VERSION 5.7 ;
  NAMESCASESENSITIVE ON ;
  NOWIREEXTENSIONATPIN ON ;
  DIVIDERCHAR "/" ;
  BUSBITCHARS "[]" ;
UNITS
  DATABASE MICRONS 200 ;
END UNITS

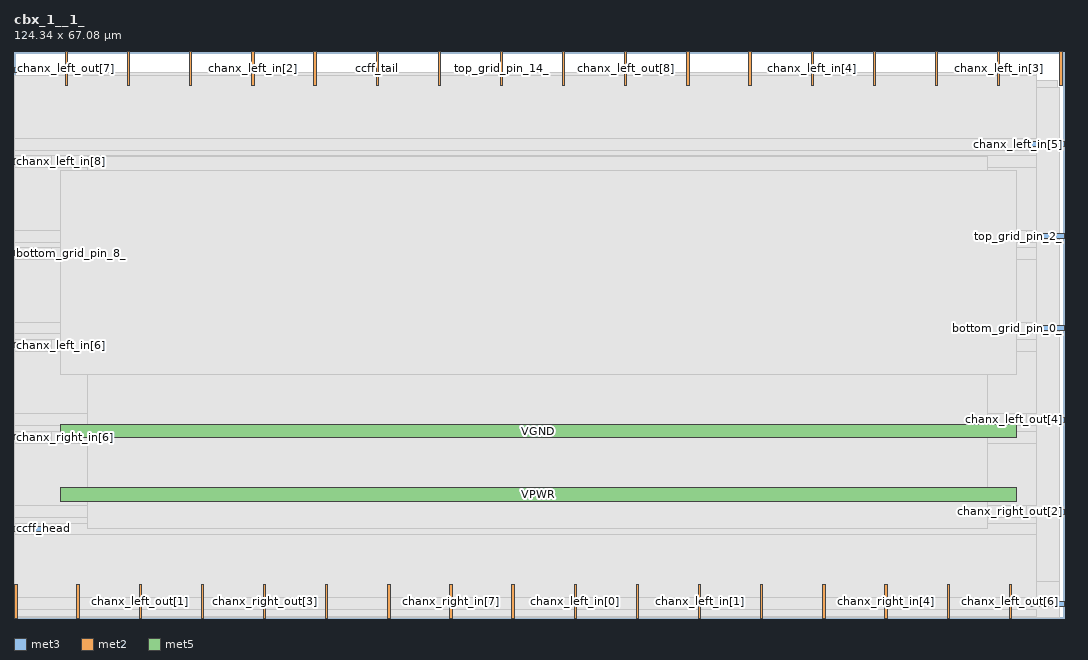
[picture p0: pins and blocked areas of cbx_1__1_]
MACRO cbx_1__1_
  CLASS BLOCK ;
  FOREIGN cbx_1__1_ ;
  ORIGIN 0.000 0.000 ;
  SIZE 124.340 BY 67.080 ;
  PIN bottom_grid_pin_0_
    DIRECTION OUTPUT TRISTATE ;
    PORT
      LAYER met3 ;
        RECT 120.340 34.040 124.340 34.640 ;
    END
  END bottom_grid_pin_0_
  PIN bottom_grid_pin_4_
    DIRECTION OUTPUT TRISTATE ;
    PORT
      LAYER met3 ;
        RECT 0.000 64.640 4.000 65.240 ;
    END
  END bottom_grid_pin_4_
  PIN bottom_grid_pin_8_
    DIRECTION OUTPUT TRISTATE ;
    PORT
      LAYER met3 ;
        RECT 0.000 42.880 4.000 43.480 ;
    END
  END bottom_grid_pin_8_
  PIN ccff_head
    DIRECTION INPUT ;
    PORT
      LAYER met3 ;
        RECT 0.000 10.240 4.000 10.840 ;
    END
  END ccff_head
  PIN ccff_tail
    DIRECTION OUTPUT TRISTATE ;
    PORT
      LAYER met2 ;
        RECT 42.870 63.080 43.150 67.080 ;
    END
  END ccff_tail
  PIN chanx_left_in[0]
    DIRECTION INPUT ;
    PORT
      LAYER met2 ;
        RECT 66.330 0.000 66.610 4.000 ;
    END
  END chanx_left_in[0]
  PIN chanx_left_in[1]
    DIRECTION INPUT ;
    PORT
      LAYER met2 ;
        RECT 81.050 0.000 81.330 4.000 ;
    END
  END chanx_left_in[1]
  PIN chanx_left_in[2]
    DIRECTION INPUT ;
    PORT
      LAYER met2 ;
        RECT 28.150 63.080 28.430 67.080 ;
    END
  END chanx_left_in[2]
  PIN chanx_left_in[3]
    DIRECTION INPUT ;
    PORT
      LAYER met2 ;
        RECT 116.470 63.080 116.750 67.080 ;
    END
  END chanx_left_in[3]
  PIN chanx_left_in[4]
    DIRECTION INPUT ;
    PORT
      LAYER met2 ;
        RECT 94.390 63.080 94.670 67.080 ;
    END
  END chanx_left_in[4]
  PIN chanx_left_in[5]
    DIRECTION INPUT ;
    PORT
      LAYER met3 ;
        RECT 120.340 55.800 124.340 56.400 ;
    END
  END chanx_left_in[5]
  PIN chanx_left_in[6]
    DIRECTION INPUT ;
    PORT
      LAYER met3 ;
        RECT 0.000 32.000 4.000 32.600 ;
    END
  END chanx_left_in[6]
  PIN chanx_left_in[7]
    DIRECTION INPUT ;
    PORT
      LAYER met2 ;
        RECT 88.410 0.000 88.690 4.000 ;
    END
  END chanx_left_in[7]
  PIN chanx_left_in[8]
    DIRECTION INPUT ;
    PORT
      LAYER met3 ;
        RECT 0.000 53.760 4.000 54.360 ;
    END
  END chanx_left_in[8]
  PIN chanx_left_out[0]
    DIRECTION OUTPUT TRISTATE ;
    PORT
      LAYER met2 ;
        RECT 50.230 63.080 50.510 67.080 ;
    END
  END chanx_left_out[0]
  PIN chanx_left_out[1]
    DIRECTION OUTPUT TRISTATE ;
    PORT
      LAYER met2 ;
        RECT 14.810 0.000 15.090 4.000 ;
    END
  END chanx_left_out[1]
  PIN chanx_left_out[2]
    DIRECTION OUTPUT TRISTATE ;
    PORT
      LAYER met3 ;
        RECT 120.340 1.400 124.340 2.000 ;
    END
  END chanx_left_out[2]
  PIN chanx_left_out[3]
    DIRECTION OUTPUT TRISTATE ;
    PORT
      LAYER met2 ;
        RECT 64.950 63.080 65.230 67.080 ;
    END
  END chanx_left_out[3]
  PIN chanx_left_out[4]
    DIRECTION OUTPUT TRISTATE ;
    PORT
      LAYER met3 ;
        RECT 120.340 23.160 124.340 23.760 ;
    END
  END chanx_left_out[4]
  PIN chanx_left_out[5]
    DIRECTION OUTPUT TRISTATE ;
    PORT
      LAYER met2 ;
        RECT 109.110 63.080 109.390 67.080 ;
    END
  END chanx_left_out[5]
  PIN chanx_left_out[6]
    DIRECTION OUTPUT TRISTATE ;
    PORT
      LAYER met2 ;
        RECT 117.850 0.000 118.130 4.000 ;
    END
  END chanx_left_out[6]
  PIN chanx_left_out[7]
    DIRECTION OUTPUT TRISTATE ;
    PORT
      LAYER met2 ;
        RECT 6.070 63.080 6.350 67.080 ;
    END
  END chanx_left_out[7]
  PIN chanx_left_out[8]
    DIRECTION OUTPUT TRISTATE ;
    PORT
      LAYER met2 ;
        RECT 72.310 63.080 72.590 67.080 ;
    END
  END chanx_left_out[8]
  PIN chanx_right_in[0]
    DIRECTION INPUT ;
    PORT
      LAYER met2 ;
        RECT 110.490 0.000 110.770 4.000 ;
    END
  END chanx_right_in[0]
  PIN chanx_right_in[1]
    DIRECTION INPUT ;
    PORT
      LAYER met2 ;
        RECT 35.510 63.080 35.790 67.080 ;
    END
  END chanx_right_in[1]
  PIN chanx_right_in[2]
    DIRECTION INPUT ;
    PORT
      LAYER met2 ;
        RECT 36.890 0.000 37.170 4.000 ;
    END
  END chanx_right_in[2]
  PIN chanx_right_in[3]
    DIRECTION INPUT ;
    PORT
      LAYER met2 ;
        RECT 20.790 63.080 21.070 67.080 ;
    END
  END chanx_right_in[3]
  PIN chanx_right_in[4]
    DIRECTION INPUT ;
    PORT
      LAYER met2 ;
        RECT 103.130 0.000 103.410 4.000 ;
    END
  END chanx_right_in[4]
  PIN chanx_right_in[5]
    DIRECTION INPUT ;
    PORT
      LAYER met2 ;
        RECT 87.030 63.080 87.310 67.080 ;
    END
  END chanx_right_in[5]
  PIN chanx_right_in[6]
    DIRECTION INPUT ;
    PORT
      LAYER met3 ;
        RECT 0.000 21.120 4.000 21.720 ;
    END
  END chanx_right_in[6]
  PIN chanx_right_in[7]
    DIRECTION INPUT ;
    PORT
      LAYER met2 ;
        RECT 51.610 0.000 51.890 4.000 ;
    END
  END chanx_right_in[7]
  PIN chanx_right_in[8]
    DIRECTION INPUT ;
    PORT
      LAYER met2 ;
        RECT 123.830 63.080 124.110 67.080 ;
    END
  END chanx_right_in[8]
  PIN chanx_right_out[0]
    DIRECTION OUTPUT TRISTATE ;
    PORT
      LAYER met2 ;
        RECT 79.670 63.080 79.950 67.080 ;
    END
  END chanx_right_out[0]
  PIN chanx_right_out[1]
    DIRECTION OUTPUT TRISTATE ;
    PORT
      LAYER met2 ;
        RECT 101.750 63.080 102.030 67.080 ;
    END
  END chanx_right_out[1]
  PIN chanx_right_out[2]
    DIRECTION OUTPUT TRISTATE ;
    PORT
      LAYER met3 ;
        RECT 120.340 12.280 124.340 12.880 ;
    END
  END chanx_right_out[2]
  PIN chanx_right_out[3]
    DIRECTION OUTPUT TRISTATE ;
    PORT
      LAYER met2 ;
        RECT 29.530 0.000 29.810 4.000 ;
    END
  END chanx_right_out[3]
  PIN chanx_right_out[4]
    DIRECTION OUTPUT TRISTATE ;
    PORT
      LAYER met2 ;
        RECT 22.170 0.000 22.450 4.000 ;
    END
  END chanx_right_out[4]
  PIN chanx_right_out[5]
    DIRECTION OUTPUT TRISTATE ;
    PORT
      LAYER met2 ;
        RECT 95.770 0.000 96.050 4.000 ;
    END
  END chanx_right_out[5]
  PIN chanx_right_out[6]
    DIRECTION OUTPUT TRISTATE ;
    PORT
      LAYER met2 ;
        RECT 73.690 0.000 73.970 4.000 ;
    END
  END chanx_right_out[6]
  PIN chanx_right_out[7]
    DIRECTION OUTPUT TRISTATE ;
    PORT
      LAYER met2 ;
        RECT 58.970 0.000 59.250 4.000 ;
    END
  END chanx_right_out[7]
  PIN chanx_right_out[8]
    DIRECTION OUTPUT TRISTATE ;
    PORT
      LAYER met2 ;
        RECT 44.250 0.000 44.530 4.000 ;
    END
  END chanx_right_out[8]
  PIN pReset
    DIRECTION INPUT ;
    PORT
      LAYER met2 ;
        RECT 13.430 63.080 13.710 67.080 ;
    END
  END pReset
  PIN prog_clk
    DIRECTION INPUT ;
    PORT
      LAYER met2 ;
        RECT 7.450 0.000 7.730 4.000 ;
    END
  END prog_clk
  PIN top_grid_pin_14_
    DIRECTION OUTPUT TRISTATE ;
    PORT
      LAYER met2 ;
        RECT 57.590 63.080 57.870 67.080 ;
    END
  END top_grid_pin_14_
  PIN top_grid_pin_2_
    DIRECTION OUTPUT TRISTATE ;
    PORT
      LAYER met3 ;
        RECT 120.340 44.920 124.340 45.520 ;
    END
  END top_grid_pin_2_
  PIN top_grid_pin_6_
    DIRECTION OUTPUT TRISTATE ;
    PORT
      LAYER met2 ;
        RECT 0.090 0.000 0.370 4.000 ;
    END
  END top_grid_pin_6_
  PIN VPWR
    DIRECTION INPUT ;
    USE POWER ;
    PORT
      LAYER met5 ;
        RECT 5.520 13.840 118.680 15.440 ;
    END
  END VPWR
  PIN VGND
    DIRECTION INPUT ;
    USE GROUND ;
    PORT
      LAYER met5 ;
        RECT 5.520 21.340 118.680 22.940 ;
    END
  END VGND
  OBS
      LAYER li1 ;
        RECT 5.520 10.795 118.680 54.485 ;
      LAYER met1 ;
        RECT 0.530 0.040 122.750 63.540 ;
      LAYER met2 ;
        RECT 0.090 62.800 5.790 63.650 ;
        RECT 6.630 62.800 13.150 63.650 ;
        RECT 13.990 62.800 20.510 63.650 ;
        RECT 21.350 62.800 27.870 63.650 ;
        RECT 28.710 62.800 35.230 63.650 ;
        RECT 36.070 62.800 42.590 63.650 ;
        RECT 43.430 62.800 49.950 63.650 ;
        RECT 50.790 62.800 57.310 63.650 ;
        RECT 58.150 62.800 64.670 63.650 ;
        RECT 65.510 62.800 72.030 63.650 ;
        RECT 72.870 62.800 79.390 63.650 ;
        RECT 80.230 62.800 86.750 63.650 ;
        RECT 87.590 62.800 94.110 63.650 ;
        RECT 94.950 62.800 101.470 63.650 ;
        RECT 102.310 62.800 108.830 63.650 ;
        RECT 109.670 62.800 116.190 63.650 ;
        RECT 117.030 62.800 123.550 63.650 ;
        RECT 0.090 4.280 123.830 62.800 ;
        RECT 0.650 0.010 7.170 4.280 ;
        RECT 8.010 0.010 14.530 4.280 ;
        RECT 15.370 0.010 21.890 4.280 ;
        RECT 22.730 0.010 29.250 4.280 ;
        RECT 30.090 0.010 36.610 4.280 ;
        RECT 37.450 0.010 43.970 4.280 ;
        RECT 44.810 0.010 51.330 4.280 ;
        RECT 52.170 0.010 58.690 4.280 ;
        RECT 59.530 0.010 66.050 4.280 ;
        RECT 66.890 0.010 73.410 4.280 ;
        RECT 74.250 0.010 80.770 4.280 ;
        RECT 81.610 0.010 88.130 4.280 ;
        RECT 88.970 0.010 95.490 4.280 ;
        RECT 96.330 0.010 102.850 4.280 ;
        RECT 103.690 0.010 110.210 4.280 ;
        RECT 111.050 0.010 117.570 4.280 ;
        RECT 118.410 0.010 123.830 4.280 ;
      LAYER met3 ;
        RECT 4.400 64.240 121.130 64.640 ;
        RECT 0.065 56.800 121.130 64.240 ;
        RECT 0.065 55.400 119.940 56.800 ;
        RECT 0.065 54.760 121.130 55.400 ;
        RECT 4.400 53.360 121.130 54.760 ;
        RECT 0.065 45.920 121.130 53.360 ;
        RECT 0.065 44.520 119.940 45.920 ;
        RECT 0.065 43.880 121.130 44.520 ;
        RECT 4.400 42.480 121.130 43.880 ;
        RECT 0.065 35.040 121.130 42.480 ;
        RECT 0.065 33.640 119.940 35.040 ;
        RECT 0.065 33.000 121.130 33.640 ;
        RECT 4.400 31.600 121.130 33.000 ;
        RECT 0.065 24.160 121.130 31.600 ;
        RECT 0.065 22.760 119.940 24.160 ;
        RECT 0.065 22.120 121.130 22.760 ;
        RECT 4.400 20.720 121.130 22.120 ;
        RECT 0.065 13.280 121.130 20.720 ;
        RECT 0.065 11.880 119.940 13.280 ;
        RECT 0.065 11.240 121.130 11.880 ;
        RECT 4.400 9.840 121.130 11.240 ;
        RECT 0.065 2.400 121.130 9.840 ;
        RECT 0.065 1.000 119.940 2.400 ;
        RECT 0.065 0.175 121.130 1.000 ;
      LAYER met4 ;
        RECT 8.720 10.640 115.320 54.640 ;
      LAYER met5 ;
        RECT 5.520 28.840 118.680 52.940 ;
  END
END cbx_1__1_
END LIBRARY

